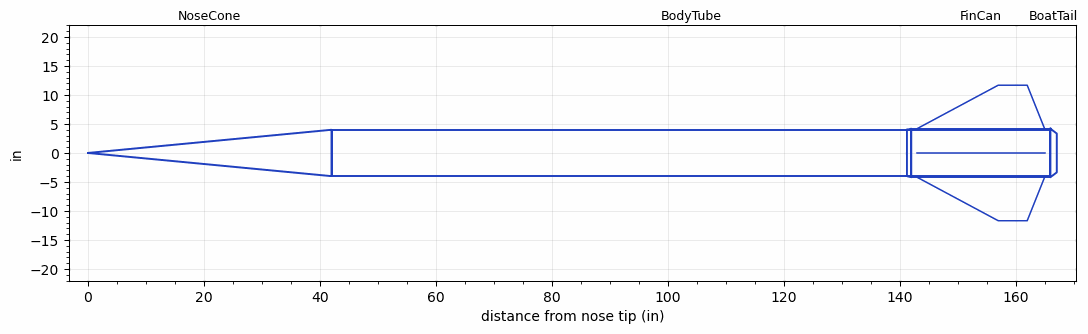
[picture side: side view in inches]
<RASAeroDocument>
 <FileVersion>2</FileVersion>
 <RocketDesign>
  <NoseCone>
   <Length>42</Length>
   <Diameter>8</Diameter>
   <Shape>Conical</Shape>
   <BluntRadius>0.0125</BluntRadius>
   <Location>0</Location>
  </NoseCone>
  <BodyTube>
   <Length>124</Length>
   <Diameter>8</Diameter>
   <Location>42</Location>
  </BodyTube>
  <FinCan>
   <Length>24</Length>
   <Diameter>8.375</Diameter>
   <InsideDiameter>8</InsideDiameter>
   <RailGuideDiameter>1.021</RailGuideDiameter>
   <RailGuideHeight>1.021</RailGuideHeight>
   <Location>166</Location>
   <ShoulderLength>0.75</ShoulderLength>
   <Offset>-24</Offset>
   <Fin>
    <Count>4</Count>
    <Chord>22</Chord>
    <Span>7.5</Span>
    <SweepDistance>14</SweepDistance>
    <TipChord>5</TipChord>
    <Thickness>0.25</Thickness>
    <LERadius>0.02</LERadius>
    <Location>23</Location>
    <AirfoilSection>Hexagonal</AirfoilSection>
    <FX1>0.75</FX1>
    <FX3>0.6</FX3>
   </Fin>
  </FinCan>
  <BoatTail>
   <Length>1.1</Length>
   <Diameter>8.375</Diameter>
   <RearDiameter>6.7</RearDiameter>
   <Location>166</Location>
  </BoatTail>
  <Surface>Smooth Paint</Surface>
  <ModifiedBarrowman>True</ModifiedBarrowman>
  <Turbulence>True</Turbulence>
  <SustainerNozzle>6</SustainerNozzle>
  <UseBooster1>False</UseBooster1>
  <UseBooster2>False</UseBooster2>
  <Comments>Qu8k Rocket
Q18000 Motor
Derek Deville
Black Rock Launch Site

Altitude Based On Integrated Accelerometer Data
Altitude = 121478 ft

Rocket landed only 3 miles from launch site.

RASAero II Prediction = 119684 ft
Error = -1.48%
</Comments>
 </RocketDesign>
 <LaunchSite>
  <Altitude>3750</Altitude>
  <Pressure>0</Pressure>
  <RodAngle>2</RodAngle>
  <RodLength>16</RodLength>
  <Temperature>80</Temperature>
  <WindSpeed>0</WindSpeed>
 </LaunchSite>
 <Recovery>
  <Altitude1>1000</Altitude1>
  <Altitude2>1000</Altitude2>
  <DeviceType1>Parachute</DeviceType1>
  <DeviceType2>None</DeviceType2>
  <Event1>True</Event1>
  <Event2>False</Event2>
  <Size1>72</Size1>
  <Size2>1</Size2>
  <EventType1>Apogee</EventType1>
  <EventType2>None</EventType2>
  <CD1>1.33</CD1>
  <CD2>1.33</CD2>
 </Recovery>
 <SimulationList>
  <Simulation>
   <SustainerEngine>Q18000  (DEAP-EX)</SustainerEngine>
   <SustainerLaunchWt>314.5</SustainerLaunchWt>
   <SustainerNozzleDiameter>6</SustainerNozzleDiameter>
   <SustainerCG>110</SustainerCG>
   <SustainerIgnitionDelay>0</SustainerIgnitionDelay>
   <Booster1SeparationDelay>0</Booster1SeparationDelay>
   <Booster1IgnitionDelay>0</Booster1IgnitionDelay>
   <IncludeBooster1>False</IncludeBooster1>
   <Booster2Delay>0</Booster2Delay>
   <IncludeBooster2>False</IncludeBooster2>
   <TimetoApogee>85.92995</TimetoApogee>
   <MaxAltitude>119683.9</MaxAltitude>
   <MaxVelocity>3752.962</MaxVelocity>
  </Simulation>
 </SimulationList>
</RASAeroDocument>
